VERSION 5.8 ;
BUSBITCHARS "[]" ;
DIVIDERCHAR "/" ;
UNITS
    DATABASE MICRONS 1000 ;
END UNITS

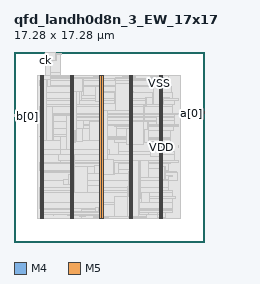
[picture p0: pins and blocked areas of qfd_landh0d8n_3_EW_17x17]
MACRO qfd_landh0d8n_3_EW_17x17
  FOREIGN qfd_landh0d8n_3_EW_17x17 0 0 ;
  CLASS BLOCK ;
  SIZE 17.28 BY 17.28 ;
  PIN a[0]
    DIRECTION INPUT ;
    USE SIGNAL ;
    PORT
      LAYER M4 ;
        RECT  17.196 11.664 17.28 11.688 ;
    END
  END a[0]
  PIN a[1]
    DIRECTION INPUT ;
    USE SIGNAL ;
    PORT
      LAYER M4 ;
        RECT  17.196 11.76 17.28 11.784 ;
    END
  END a[1]
  PIN a[2]
    DIRECTION INPUT ;
    USE SIGNAL ;
    PORT
      LAYER M4 ;
        RECT  17.196 11.856 17.28 11.88 ;
    END
  END a[2]
  PIN b[0]
    DIRECTION OUTPUT ;
    USE SIGNAL ;
    PORT
      LAYER M4 ;
        RECT  0 11.376 0.084 11.4 ;
    END
  END b[0]
  PIN b[1]
    DIRECTION OUTPUT ;
    USE SIGNAL ;
    PORT
      LAYER M4 ;
        RECT  0 11.472 0.084 11.496 ;
    END
  END b[1]
  PIN b[2]
    DIRECTION OUTPUT ;
    USE SIGNAL ;
    PORT
      LAYER M4 ;
        RECT  0 11.568 0.084 11.592 ;
    END
  END b[2]
  PIN ck
    DIRECTION INPUT ;
    USE SIGNAL ;
    PORT
      LAYER M5 ;
        RECT  2.832 17.196 2.856 17.28 ;
    END
  END ck
  PIN ck_s
    DIRECTION INPUT ;
    USE SIGNAL ;
    PORT
      LAYER M5 ;
        RECT  2.928 17.196 2.952 17.28 ;
    END
  END ck_s
  PIN en
    DIRECTION INPUT ;
    USE SIGNAL ;
    PORT
      LAYER M5 ;
        RECT  3.024 17.196 3.048 17.28 ;
    END
  END en
  PIN fault
    DIRECTION OUTPUT ;
    USE SIGNAL ;
    PORT
      LAYER M5 ;
        RECT  3.12 17.196 3.144 17.28 ;
    END
  END fault
  PIN k0
    DIRECTION INPUT ;
    USE SIGNAL ;
    PORT
      LAYER M5 ;
        RECT  3.216 17.196 3.24 17.28 ;
    END
  END k0
  PIN k1
    DIRECTION INPUT ;
    USE SIGNAL ;
    PORT
      LAYER M5 ;
        RECT  3.312 17.196 3.336 17.28 ;
    END
  END k1
  PIN k2
    DIRECTION INPUT ;
    USE SIGNAL ;
    PORT
      LAYER M5 ;
        RECT  3.408 17.196 3.432 17.28 ;
    END
  END k2
  PIN k3
    DIRECTION INPUT ;
    USE SIGNAL ;
    PORT
      LAYER M5 ;
        RECT  3.504 17.196 3.528 17.28 ;
    END
  END k3
  PIN rs
    DIRECTION INPUT ;
    USE SIGNAL ;
    PORT
      LAYER M5 ;
        RECT  3.6 17.196 3.624 17.28 ;
    END
  END rs
  PIN tie_hi
    DIRECTION OUTPUT ;
    USE SIGNAL ;
    PORT
      LAYER M5 ;
        RECT  3.696 17.196 3.72 17.28 ;
    END
  END tie_hi
  PIN tie_lo
    DIRECTION OUTPUT ;
    USE SIGNAL ;
    PORT
      LAYER M5 ;
        RECT  3.792 17.196 3.816 17.28 ;
    END
  END tie_lo
  PIN VDD
    DIRECTION INOUT ;
    USE POWER ;
    PORT
      LAYER M5 ;
        RECT  13.392 2.151 13.512 15.129 ;
        RECT  10.692 2.151 10.812 15.129 ;
        RECT  7.992 2.151 8.112 15.129 ;
        RECT  5.292 2.151 5.412 15.129 ;
        RECT  2.592 2.151 2.712 15.129 ;
    END
  END VDD
  PIN VSS
    DIRECTION INOUT ;
    USE GROUND ;
    PORT
      LAYER M5 ;
        RECT  13.2 2.137 13.32 15.143 ;
        RECT  10.5 2.137 10.62 15.143 ;
        RECT  7.8 2.137 7.92 15.143 ;
        RECT  5.1 2.137 5.22 15.143 ;
        RECT  2.4 2.137 2.52 15.143 ;
    END
  END VSS
  OBS
    LAYER RVTN ;
     RECT  2.16 2.16 15.12 2.295 ;
     RECT  2.16 2.565 15.12 2.835 ;
     RECT  2.16 3.105 15.12 3.375 ;
     RECT  2.16 3.645 15.12 3.915 ;
     RECT  2.16 4.185 15.12 4.455 ;
     RECT  2.16 4.725 15.12 4.995 ;
     RECT  2.16 5.265 15.12 5.535 ;
     RECT  2.16 5.805 15.12 6.075 ;
     RECT  2.16 6.345 15.12 6.615 ;
     RECT  2.16 6.885 15.12 7.155 ;
     RECT  2.16 7.425 15.12 7.695 ;
     RECT  2.16 7.965 15.12 8.235 ;
     RECT  2.16 8.505 15.12 8.775 ;
     RECT  2.16 9.045 15.12 9.315 ;
     RECT  2.16 9.585 15.12 9.855 ;
     RECT  2.16 10.125 15.12 10.395 ;
     RECT  2.16 10.665 15.12 10.935 ;
     RECT  2.16 11.205 15.12 11.475 ;
     RECT  2.16 11.745 15.12 12.015 ;
     RECT  2.16 12.285 15.12 12.555 ;
     RECT  2.16 12.825 15.12 13.095 ;
     RECT  2.16 13.365 15.12 13.635 ;
     RECT  2.16 13.905 15.12 14.175 ;
     RECT  2.16 14.445 15.12 14.715 ;
     RECT  2.16 14.985 15.12 15.12 ;
    LAYER RVTP ;
     RECT  2.16 2.295 15.12 2.565 ;
     RECT  2.16 2.835 15.12 3.105 ;
     RECT  2.16 3.375 15.12 3.645 ;
     RECT  2.16 3.915 15.12 4.185 ;
     RECT  2.16 4.455 15.12 4.725 ;
     RECT  2.16 4.995 15.12 5.265 ;
     RECT  2.16 5.535 15.12 5.805 ;
     RECT  2.16 6.075 15.12 6.345 ;
     RECT  2.16 6.615 15.12 6.885 ;
     RECT  2.16 7.155 15.12 7.425 ;
     RECT  2.16 7.695 15.12 7.965 ;
     RECT  2.16 8.235 15.12 8.505 ;
     RECT  2.16 8.775 15.12 9.045 ;
     RECT  2.16 9.315 15.12 9.585 ;
     RECT  2.16 9.855 15.12 10.125 ;
     RECT  2.16 10.395 15.12 10.665 ;
     RECT  2.16 10.935 15.12 11.205 ;
     RECT  2.16 11.475 15.12 11.745 ;
     RECT  2.16 12.015 15.12 12.285 ;
     RECT  2.16 12.555 15.12 12.825 ;
     RECT  2.16 13.095 15.12 13.365 ;
     RECT  2.16 13.635 15.12 13.905 ;
     RECT  2.16 14.175 15.12 14.445 ;
     RECT  2.16 14.715 15.12 14.985 ;
    LAYER M1 ;
     RECT  2.16 2.151 15.12 15.129 ;
    LAYER M2 ;
     RECT  2.16 2.151 15.12 15.129 ;
     RECT  15.12 11.718 16.547 11.934 ;
     RECT  16.547 11.718 17.195 11.736 ;
    LAYER M3 ;
     RECT  7.815 2.143 7.905 2.191 ;
     RECT  10.515 2.143 10.605 2.191 ;
     RECT  13.215 2.143 13.305 2.191 ;
     RECT  7.272 2.191 7.905 2.227 ;
     RECT  10.368 2.191 10.605 2.227 ;
     RECT  13.215 2.191 13.734 2.227 ;
     RECT  7.272 2.227 8.37 2.263 ;
     RECT  10.368 2.227 11.286 2.263 ;
     RECT  12.024 2.191 12.042 2.263 ;
     RECT  6.12 2.263 6.138 2.299 ;
     RECT  7.272 2.263 8.586 2.299 ;
     RECT  10.368 2.263 12.042 2.299 ;
     RECT  5.94 2.299 6.138 2.335 ;
     RECT  10.296 2.299 12.042 2.335 ;
     RECT  5.115 2.143 5.205 2.371 ;
     RECT  5.94 2.335 6.498 2.371 ;
     RECT  7.272 2.299 9.234 2.371 ;
     RECT  2.415 2.143 2.505 2.413 ;
     RECT  2.415 2.413 2.697 2.461 ;
     RECT  3.6 2.371 3.618 2.461 ;
     RECT  10.152 2.335 12.042 2.491 ;
     RECT  2.415 2.461 3.906 2.497 ;
     RECT  4.896 2.371 9.306 2.497 ;
     RECT  2.415 2.497 9.306 2.641 ;
     RECT  10.152 2.491 12.258 2.641 ;
     RECT  13.032 2.227 13.734 2.641 ;
     RECT  10.152 2.641 14.454 2.839 ;
     RECT  2.415 2.641 9.378 2.911 ;
     RECT  10.116 2.839 14.454 2.911 ;
     RECT  2.415 2.911 14.454 3.019 ;
     RECT  2.34 3.019 14.454 3.569 ;
     RECT  12.312 3.569 14.454 3.955 ;
     RECT  12.312 3.955 14.67 4.109 ;
     RECT  2.34 3.569 11.574 4.495 ;
     RECT  12.312 4.109 14.382 4.495 ;
     RECT  2.34 4.495 14.382 4.721 ;
     RECT  2.34 4.721 14.058 4.991 ;
     RECT  2.415 4.991 14.058 5.611 ;
     RECT  2.415 5.611 14.886 6.305 ;
     RECT  2.415 6.305 14.742 6.377 ;
     RECT  2.415 6.377 14.094 6.547 ;
     RECT  2.34 6.547 14.094 7.159 ;
     RECT  2.34 7.159 14.274 7.195 ;
     RECT  2.34 7.195 14.562 7.229 ;
     RECT  2.415 7.229 14.562 7.231 ;
     RECT  2.415 7.231 14.994 7.421 ;
     RECT  2.415 7.421 14.634 7.925 ;
     RECT  9.432 7.925 14.634 7.961 ;
     RECT  9.468 7.961 14.634 8.195 ;
     RECT  2.415 7.925 8.658 8.429 ;
     RECT  14.976 8.581 14.994 8.771 ;
     RECT  9.468 8.195 14.202 9.049 ;
     RECT  2.415 8.429 8.262 9.349 ;
     RECT  9.144 9.049 14.202 9.349 ;
     RECT  2.415 9.349 14.202 9.391 ;
     RECT  2.376 9.391 14.202 9.545 ;
     RECT  2.376 9.545 8.406 9.589 ;
     RECT  2.34 9.589 8.406 9.629 ;
     RECT  2.376 9.629 8.406 9.779 ;
     RECT  9.324 9.545 14.202 10.165 ;
     RECT  2.415 9.779 8.406 10.319 ;
     RECT  9.324 10.165 14.526 10.471 ;
     RECT  6.336 10.319 8.406 10.561 ;
     RECT  9.144 10.471 14.994 10.561 ;
     RECT  6.336 10.561 14.994 10.661 ;
     RECT  2.415 10.319 5.562 11.083 ;
     RECT  6.336 10.661 14.598 11.083 ;
     RECT  2.415 11.083 14.598 11.281 ;
     RECT  2.304 11.281 14.598 11.405 ;
     RECT  2.34 11.405 14.598 11.551 ;
     RECT  2.34 11.551 14.922 11.669 ;
     RECT  2.34 11.669 14.418 11.705 ;
     RECT  16.524 11.659 16.542 11.713 ;
     RECT  16.524 11.713 17.19 11.789 ;
     RECT  16.524 11.789 16.542 11.939 ;
     RECT  2.34 11.705 14.382 12.365 ;
     RECT  2.415 12.365 14.382 12.523 ;
     RECT  2.415 12.523 14.562 12.901 ;
     RECT  2.415 12.901 14.994 13.055 ;
     RECT  2.415 13.055 14.382 13.559 ;
     RECT  2.415 13.559 14.346 14.099 ;
     RECT  2.415 14.099 14.202 14.135 ;
     RECT  2.415 14.135 14.058 14.203 ;
     RECT  2.34 14.203 14.058 14.711 ;
     RECT  2.415 14.711 14.058 14.909 ;
     RECT  2.415 14.909 7.905 14.945 ;
     RECT  9.216 14.909 11.07 14.945 ;
     RECT  12.42 14.909 14.058 14.945 ;
     RECT  6.588 14.945 7.905 14.981 ;
     RECT  12.42 14.945 13.305 15.017 ;
     RECT  14.04 14.945 14.058 15.017 ;
     RECT  9.828 14.945 11.07 15.053 ;
     RECT  2.415 14.945 5.205 15.089 ;
     RECT  7.272 14.981 7.905 15.089 ;
     RECT  12.816 15.017 13.305 15.089 ;
     RECT  2.415 15.089 4.266 15.137 ;
     RECT  5.115 15.089 5.205 15.137 ;
     RECT  7.815 15.089 7.905 15.137 ;
     RECT  10.515 15.053 10.605 15.137 ;
     RECT  13.215 15.089 13.305 15.137 ;
     RECT  3.06 15.137 4.266 15.389 ;
     RECT  3.24 15.389 4.266 17.069 ;
     RECT  3.24 17.069 3.438 17.117 ;
     RECT  4.176 17.069 4.266 17.117 ;
     RECT  4.176 17.117 4.194 17.165 ;
    LAYER M4 ;
     RECT  0.06 11.376 2.329 11.592 ;
     RECT  2.329 3.024 2.408 3.048 ;
     RECT  2.329 4.656 2.408 4.68 ;
     RECT  2.329 7.2 2.408 7.224 ;
     RECT  2.329 9.6 2.408 9.624 ;
     RECT  2.329 11.376 2.408 12.36 ;
     RECT  2.329 14.208 2.408 14.232 ;
     RECT  2.408 2.148 2.512 15.132 ;
     RECT  2.512 2.418 2.704 15.132 ;
     RECT  2.704 14.112 3.005 15.132 ;
     RECT  3.005 14.112 3.089 15.384 ;
     RECT  3.109 17.136 3.185 17.16 ;
     RECT  3.089 14.112 3.347 14.856 ;
     RECT  3.185 17.088 3.493 17.16 ;
     RECT  3.493 17.04 3.517 17.16 ;
     RECT  2.704 9.264 3.521 12.36 ;
     RECT  3.521 9.264 3.629 11.496 ;
     RECT  3.517 16.512 3.827 17.16 ;
     RECT  3.827 16.944 3.881 17.16 ;
     RECT  2.704 4.656 4.061 4.68 ;
     RECT  3.881 17.088 4.205 17.16 ;
     RECT  2.704 7.2 4.213 7.992 ;
     RECT  3.629 9.264 4.213 9.624 ;
     RECT  4.205 17.088 4.277 17.112 ;
     RECT  4.489 5.664 4.525 5.688 ;
     RECT  3.629 10.944 4.741 11.496 ;
     RECT  4.213 7.2 4.777 9.624 ;
     RECT  4.741 10.848 4.777 11.496 ;
     RECT  4.525 5.232 4.921 5.688 ;
     RECT  2.704 3.024 5.108 3.048 ;
     RECT  4.921 5.232 5.108 6.12 ;
     RECT  4.777 7.2 5.108 11.496 ;
     RECT  4.201 12.864 5.108 12.888 ;
     RECT  3.347 14.112 5.108 14.232 ;
     RECT  5.108 2.148 5.212 15.132 ;
     RECT  5.212 2.418 5.404 14.862 ;
     RECT  5.404 4.512 5.501 7.992 ;
     RECT  5.404 9.024 5.537 11.496 ;
     RECT  5.537 9.024 5.609 11.448 ;
     RECT  5.609 9.12 5.651 11.448 ;
     RECT  5.651 11.424 5.933 11.448 ;
     RECT  5.404 12.528 5.933 14.856 ;
     RECT  5.404 2.736 6.113 3.048 ;
     RECT  5.933 12.864 6.113 14.856 ;
     RECT  5.651 9.12 6.257 10.344 ;
     RECT  6.113 13.296 6.293 14.856 ;
     RECT  5.501 4.512 6.689 6.84 ;
     RECT  6.257 9.264 6.901 10.344 ;
     RECT  6.689 6.24 7.297 6.84 ;
     RECT  6.113 2.736 7.369 2.808 ;
     RECT  6.293 13.296 7.369 14.136 ;
     RECT  7.369 2.736 7.729 3.096 ;
     RECT  7.369 12.768 7.765 14.136 ;
     RECT  7.729 2.736 7.808 3.144 ;
     RECT  6.689 4.512 7.808 5.16 ;
     RECT  7.297 6.24 7.808 6.936 ;
     RECT  5.501 7.968 7.808 7.992 ;
     RECT  6.901 9.264 7.808 10.968 ;
     RECT  7.765 12 7.808 14.136 ;
     RECT  7.808 2.148 7.912 15.132 ;
     RECT  7.912 2.304 8.104 14.862 ;
     RECT  8.104 9.264 8.165 10.872 ;
     RECT  8.165 9.264 8.201 9.576 ;
     RECT  8.201 9.36 8.531 9.576 ;
     RECT  8.165 10.848 8.531 10.872 ;
     RECT  8.104 6.144 9.059 7.464 ;
     RECT  8.104 2.304 9.097 3.432 ;
     RECT  9.059 6.144 9.1 7.224 ;
     RECT  8.104 12 9.164 12.552 ;
     RECT  8.104 13.68 9.164 13.704 ;
     RECT  9.164 12 9.205 13.704 ;
     RECT  9.164 14.784 9.205 14.808 ;
     RECT  9.205 11.952 9.251 14.808 ;
     RECT  8.531 9.552 9.313 9.576 ;
     RECT  9.1 6.192 9.497 7.224 ;
     RECT  9.313 9.552 10.249 10.344 ;
     RECT  9.097 2.304 10.357 4.104 ;
     RECT  10.357 2.304 10.508 5.064 ;
     RECT  9.497 6.192 10.508 6.6 ;
     RECT  10.249 8.832 10.508 10.344 ;
     RECT  9.251 11.952 10.508 14.376 ;
     RECT  10.508 2.148 10.612 15.132 ;
     RECT  10.612 2.304 10.804 14.862 ;
     RECT  10.804 13.632 10.829 13.656 ;
     RECT  10.804 2.304 11.297 7.416 ;
     RECT  11.297 2.496 11.369 7.416 ;
     RECT  11.369 3.936 11.513 7.416 ;
     RECT  10.804 8.832 11.797 10.92 ;
     RECT  11.797 8.832 11.801 12.408 ;
     RECT  11.801 9.072 11.881 12.408 ;
     RECT  11.881 12.384 11.989 12.408 ;
     RECT  11.989 12.384 12.035 13.128 ;
     RECT  12.035 12.48 12.085 13.128 ;
     RECT  11.881 9.072 12.197 10.92 ;
     RECT  11.513 5.904 12.233 7.416 ;
     RECT  12.085 12.48 12.625 13.176 ;
     RECT  12.625 12.48 12.661 13.608 ;
     RECT  10.804 14.784 12.661 14.808 ;
     RECT  12.197 10.704 12.985 10.92 ;
     RECT  12.421 7.776 13.093 7.8 ;
     RECT  11.369 2.496 13.208 2.52 ;
     RECT  11.513 4.512 13.208 4.92 ;
     RECT  12.233 5.904 13.208 6.648 ;
     RECT  13.093 7.776 13.208 7.944 ;
     RECT  12.197 9.072 13.208 9.096 ;
     RECT  12.985 10.704 13.208 11.4 ;
     RECT  12.661 12.48 13.208 14.808 ;
     RECT  13.208 2.148 13.312 15.132 ;
     RECT  13.312 2.418 13.504 14.862 ;
     RECT  13.504 7.92 13.637 7.992 ;
     RECT  13.504 12.48 13.637 13.176 ;
     RECT  13.504 2.832 13.709 2.856 ;
     RECT  13.504 10.704 13.709 10.728 ;
     RECT  13.637 13.056 13.709 13.176 ;
     RECT  13.504 5.664 13.753 6.888 ;
     RECT  13.753 5.664 13.781 6.6 ;
     RECT  13.781 5.664 14.033 6.024 ;
     RECT  13.637 7.968 14.033 7.992 ;
     RECT  13.709 13.152 14.141 13.176 ;
     RECT  14.033 6 14.393 6.024 ;
     RECT  16.513 11.664 17.244 11.88 ;
    LAYER M5 ;
     RECT  2.4 2.137 2.52 2.151 ;
     RECT  5.1 2.137 5.22 2.151 ;
     RECT  7.8 2.137 7.92 2.151 ;
     RECT  10.5 2.137 10.62 2.151 ;
     RECT  13.2 2.137 13.32 2.151 ;
     RECT  10.5 2.151 10.812 2.293 ;
     RECT  10.32 2.293 10.812 4.115 ;
     RECT  5.1 2.151 5.412 4.933 ;
     RECT  13.2 2.151 13.512 5.653 ;
     RECT  7.8 2.151 8.112 6.133 ;
     RECT  5.1 4.933 5.544 6.419 ;
     RECT  10.368 4.115 10.812 6.419 ;
     RECT  13.2 5.653 13.704 6.899 ;
     RECT  5.1 6.419 5.412 7.189 ;
     RECT  4.224 7.189 5.412 7.381 ;
     RECT  7.8 6.133 9.048 7.475 ;
     RECT  13.2 6.899 13.512 7.765 ;
     RECT  4.032 7.381 5.412 8.003 ;
     RECT  4.224 8.003 5.412 8.435 ;
     RECT  12.432 7.765 13.512 9.107 ;
     RECT  2.4 2.151 2.712 9.253 ;
     RECT  5.1 8.435 5.412 10.165 ;
     RECT  11.808 9.541 11.832 10.213 ;
     RECT  11.808 10.213 12.12 10.931 ;
     RECT  11.808 10.931 11.832 11.459 ;
     RECT  7.8 7.475 8.52 11.941 ;
     RECT  7.8 11.941 9.24 12.563 ;
     RECT  12 12.373 12.024 13.139 ;
     RECT  5.1 10.165 5.64 13.669 ;
     RECT  9.216 12.563 9.24 14.819 ;
     RECT  2.4 9.253 2.952 14.821 ;
     RECT  5.1 13.669 6.264 14.867 ;
     RECT  5.1 14.867 5.412 15.129 ;
     RECT  7.8 12.563 8.112 15.129 ;
     RECT  10.5 6.419 10.812 15.129 ;
     RECT  13.2 9.107 13.512 15.129 ;
     RECT  2.4 14.821 3.336 15.143 ;
     RECT  5.1 15.129 5.22 15.143 ;
     RECT  7.8 15.129 7.92 15.143 ;
     RECT  10.5 15.129 10.62 15.143 ;
     RECT  13.2 15.129 13.32 15.143 ;
     RECT  2.832 15.143 3.336 16.501 ;
     RECT  2.832 16.501 3.816 17.232 ;
  END
END qfd_landh0d8n_3_EW_17x17
END LIBRARY
